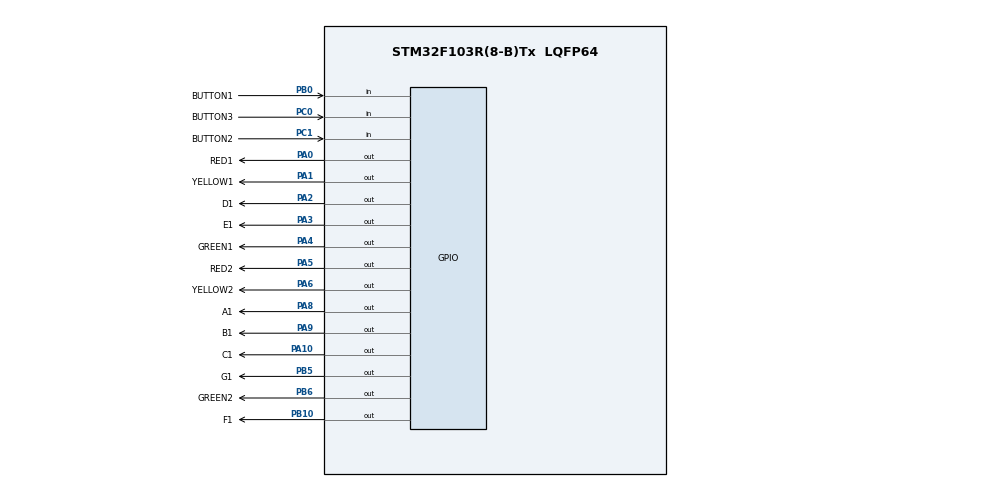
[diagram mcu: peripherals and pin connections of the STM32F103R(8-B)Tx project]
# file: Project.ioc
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Mcu.Family=STM32F1
Mcu.Name=STM32F103R(8-B)Tx
Mcu.Package=LQFP64
NVIC.PriorityGroup=NVIC_PRIORITYGROUP_4
NVIC.TIM2_IRQn=true\:0\:0\:false\:false\:true\:true\:true\:true
PA0-WKUP.GPIO_Label=RED1
PA0-WKUP.Signal=GPIO_Output
PA1.GPIO_Label=YELLOW1
PA1.Signal=GPIO_Output
PA10.GPIO_Label=C1
PA10.GPIO_Speed=GPIO_SPEED_FREQ_LOW
PA10.PinState=GPIO_PIN_SET
PA10.Signal=GPIO_Output
PA2.GPIO_Label=D1
PA2.GPIO_Speed=GPIO_SPEED_FREQ_LOW
PA2.PinState=GPIO_PIN_SET
PA2.Signal=GPIO_Output
PA3.GPIO_Label=E1
PA3.GPIO_Speed=GPIO_SPEED_FREQ_LOW
PA3.PinState=GPIO_PIN_SET
PA3.Signal=GPIO_Output
PA4.GPIO_Label=GREEN1
PA4.Signal=GPIO_Output
PA5.GPIO_Label=RED2
PA5.Signal=GPIO_Output
PA6.GPIO_Label=YELLOW2
PA6.Signal=GPIO_Output
PA8.GPIO_Label=A1
PA8.GPIO_Speed=GPIO_SPEED_FREQ_LOW
PA8.PinState=GPIO_PIN_SET
PA8.Signal=GPIO_Output
PA9.GPIO_Label=B1
PA9.GPIO_Speed=GPIO_SPEED_FREQ_LOW
PA9.PinState=GPIO_PIN_SET
PA9.Signal=GPIO_Output
PB0.GPIO_Label=BUTTON1
PB0.GPIO_PuPd=GPIO_PULLUP
PB0.Signal=GPIO_Input
PB10.GPIO_Label=F1
PB10.GPIO_Speed=GPIO_SPEED_FREQ_LOW
PB10.PinState=GPIO_PIN_SET
PB10.Signal=GPIO_Output
PB5.GPIO_Label=G1
PB5.GPIO_Speed=GPIO_SPEED_FREQ_LOW
PB5.PinState=GPIO_PIN_SET
PB5.Signal=GPIO_Output
PB6.GPIO_Label=GREEN2
PB6.GPIO_Speed=GPIO_SPEED_FREQ_LOW
PB6.PinState=GPIO_PIN_SET
PB6.Signal=GPIO_Output
PC0.GPIO_Label=BUTTON3
PC0.GPIO_PuPd=GPIO_PULLUP
PC0.Signal=GPIO_Input
PC1.GPIO_Label=BUTTON2
PC1.GPIO_PuPd=GPIO_PULLUP
PC1.Signal=GPIO_Input
ProjectManager.HeapSize=0x200
ProjectManager.StackSize=0x400
ProjectManager.TargetToolchain=STM32CubeIDE
RCC.APB1Freq_Value=8000000
RCC.APB2Freq_Value=8000000
TIM2.Period=10
TIM2.Prescaler=7999
VP_TIM2_VS_ClockSourceINT.Mode=Internal
board=custom

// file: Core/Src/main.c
/* USER CODE BEGIN Header */
/**
  ******************************************************************************
  * @file           : main.c
  * @brief          :    	E Main program body
  ******************************************************************************
  * @attention
  *
  * Copyright (c) 2023 STMicroelectronics.
  * All rights reserved.
  *
  * This software is licensed under terms that can be found in the LICENSE file
  * in the root directory of this software component.
  * If no LICENSE file comes with this software, it is provided AS-IS.
  *
  ******************************************************************************
  */
/* USER CODE END Header */
#include "main.h"

/* USER CODE BEGIN Includes */
#include "button.h"
#include "software_timer.h"
#include "fsm_auto.h"
#include "fsm_manual.h"
#include "global.h"
#include "display_led.h"
/* USER CODE END Includes */

TIM_HandleTypeDef htim2;

void SystemClock_Config(void);
static void MX_GPIO_Init(void);
static void MX_TIM2_Init(void);

int main(void)
{

  /* MCU Configuration--------------------------------------------------------*/

  /* Reset of all peripherals, Initializes the Flash interface and the Systick. */
  HAL_Init();

  /* Configure the system clock */
  SystemClock_Config();

  /* Initialize all configured peripherals */
  MX_GPIO_Init();
  MX_TIM2_Init();
  /* USER CODE BEGIN 2 */
  HAL_TIM_Base_Start_IT(&htim2);
  setValues();
  setTimer(0, 100);
  setTimer(1, 25);
  /* USER CODE END 2 */

  /* Infinite loop */
  while (1)
  {

    /* USER CODE BEGIN 3 */
	  auto_run();
	  manual_run();
  }
  /* USER CODE END 3 */
}

void SystemClock_Config(void)
{
  RCC_OscInitTypeDef RCC_OscInitStruct = {0};
  RCC_ClkInitTypeDef RCC_ClkInitStruct = {0};

  /** Initializes the RCC Oscillators according to the specified parameters
  * in the RCC_OscInitTypeDef structure.
  */
  RCC_OscInitStruct.OscillatorType = RCC_OSCILLATORTYPE_HSI;
  RCC_OscInitStruct.HSIState = RCC_HSI_ON;
  RCC_OscInitStruct.HSICalibrationValue = RCC_HSICALIBRATION_DEFAULT;
  RCC_OscInitStruct.PLL.PLLState = RCC_PLL_NONE;
  if (HAL_RCC_OscConfig(&RCC_OscInitStruct) != HAL_OK)
  {
    Error_Handler();
  }

  /** Initializes the CPU, AHB and APB buses clocks
  */
  RCC_ClkInitStruct.ClockType = RCC_CLOCKTYPE_HCLK|RCC_CLOCKTYPE_SYSCLK
                              |RCC_CLOCKTYPE_PCLK1|RCC_CLOCKTYPE_PCLK2;
  RCC_ClkInitStruct.SYSCLKSource = RCC_SYSCLKSOURCE_HSI;
  RCC_ClkInitStruct.AHBCLKDivider = RCC_SYSCLK_DIV1;
  RCC_ClkInitStruct.APB1CLKDivider = RCC_HCLK_DIV1;
  RCC_ClkInitStruct.APB2CLKDivider = RCC_HCLK_DIV1;

  if (HAL_RCC_ClockConfig(&RCC_ClkInitStruct, FLASH_LATENCY_0) != HAL_OK)
  {
    Error_Handler();
  }
}

static void MX_TIM2_Init(void)
{

  TIM_ClockConfigTypeDef sClockSourceConfig = {0};
  TIM_MasterConfigTypeDef sMasterConfig = {0};

  htim2.Instance = TIM2;
  htim2.Init.Prescaler = 7999;
  htim2.Init.CounterMode = TIM_COUNTERMODE_UP;
  htim2.Init.Period = 10;
  htim2.Init.ClockDivision = TIM_CLOCKDIVISION_DIV1;
  htim2.Init.AutoReloadPreload = TIM_AUTORELOAD_PRELOAD_DISABLE;
  if (HAL_TIM_Base_Init(&htim2) != HAL_OK)
  {
    Error_Handler();
  }
  sClockSourceConfig.ClockSource = TIM_CLOCKSOURCE_INTERNAL;
  if (HAL_TIM_ConfigClockSource(&htim2, &sClockSourceConfig) != HAL_OK)
  {
    Error_Handler();
  }
  sMasterConfig.MasterOutputTrigger = TIM_TRGO_RESET;
  sMasterConfig.MasterSlaveMode = TIM_MASTERSLAVEMODE_DISABLE;
  if (HAL_TIMEx_MasterConfigSynchronization(&htim2, &sMasterConfig) != HAL_OK)
  {
    Error_Handler();
  }

}

static void MX_GPIO_Init(void)
{
  GPIO_InitTypeDef GPIO_InitStruct = {0};

  /* GPIO Ports Clock Enable */
  __HAL_RCC_GPIOC_CLK_ENABLE();
  __HAL_RCC_GPIOA_CLK_ENABLE();
  __HAL_RCC_GPIOB_CLK_ENABLE();

  /*Configure GPIO pin Output Level */
  HAL_GPIO_WritePin(GPIOA, LED_Pin|EN4_Pin|EN3_Pin|GPIO_PIN_7, GPIO_PIN_RESET);

  /*Configure GPIO pin Output Level */
  HAL_GPIO_WritePin(GPIOA, D1_Pin|E1_Pin|A1_Pin|B1_Pin
                          |C1_Pin, GPIO_PIN_SET);

  /*Configure GPIO pin Output Level */
  HAL_GPIO_WritePin(GPIOB, F1_Pin|G1_Pin|EN2_Pin, GPIO_PIN_SET);

  /*Configure GPIO pin Output Level */
  HAL_GPIO_WritePin(EN1_GPIO_Port, EN1_Pin, GPIO_PIN_RESET);

  /*Configure GPIO pins : BUTTON3_Pin BUTTON2_Pin */
  GPIO_InitStruct.Pin = BUTTON3_Pin|BUTTON2_Pin;
  GPIO_InitStruct.Mode = GPIO_MODE_INPUT;
  GPIO_InitStruct.Pull = GPIO_PULLUP;
  HAL_GPIO_Init(GPIOC, &GPIO_InitStruct);

  /*Configure GPIO pins : LED_Pin D1_Pin E1_Pin EN4_Pin
                           EN3_Pin PA7 A1_Pin B1_Pin
                           C1_Pin */
  GPIO_InitStruct.Pin = LED_Pin|D1_Pin|E1_Pin|EN4_Pin
                          |EN3_Pin|GPIO_PIN_7|A1_Pin|B1_Pin
                          |C1_Pin;
  GPIO_InitStruct.Mode = GPIO_MODE_OUTPUT_PP;
  GPIO_InitStruct.Pull = GPIO_NOPULL;
  GPIO_InitStruct.Speed = GPIO_SPEED_FREQ_LOW;
  HAL_GPIO_Init(GPIOA, &GPIO_InitStruct);

  /*Configure GPIO pin : BUTTON1_Pin */
  GPIO_InitStruct.Pin = BUTTON1_Pin;
  GPIO_InitStruct.Mode = GPIO_MODE_INPUT;
  GPIO_InitStruct.Pull = GPIO_PULLUP;
  HAL_GPIO_Init(BUTTON1_GPIO_Port, &GPIO_InitStruct);

  /*Configure GPIO pins : F1_Pin G1_Pin EN2_Pin */
  GPIO_InitStruct.Pin = F1_Pin|G1_Pin|EN2_Pin;
  GPIO_InitStruct.Mode = GPIO_MODE_OUTPUT_PP;
  GPIO_InitStruct.Pull = GPIO_NOPULL;
  GPIO_InitStruct.Speed = GPIO_SPEED_FREQ_LOW;
  HAL_GPIO_Init(GPIOB, &GPIO_InitStruct);

  /*Configure GPIO pin : EN1_Pin */
  GPIO_InitStruct.Pin = EN1_Pin;
  GPIO_InitStruct.Mode = GPIO_MODE_OUTPUT_PP;
  GPIO_InitStruct.Pull = GPIO_NOPULL;
  GPIO_InitStruct.Speed = GPIO_SPEED_FREQ_LOW;
  HAL_GPIO_Init(EN1_GPIO_Port, &GPIO_InitStruct);

}

/* USER CODE BEGIN 4 */
void HAL_TIM_PeriodElapsedCallback(TIM_HandleTypeDef *htim){
	getKeyInput();
	timerRun(0);
	timerRun(1);
	timerRun(2);
	timerRun(3);
}
/* USER CODE END 4 */

void Error_Handler(void)
{
  __disable_irq();
  while (1)
  {
  }
}
